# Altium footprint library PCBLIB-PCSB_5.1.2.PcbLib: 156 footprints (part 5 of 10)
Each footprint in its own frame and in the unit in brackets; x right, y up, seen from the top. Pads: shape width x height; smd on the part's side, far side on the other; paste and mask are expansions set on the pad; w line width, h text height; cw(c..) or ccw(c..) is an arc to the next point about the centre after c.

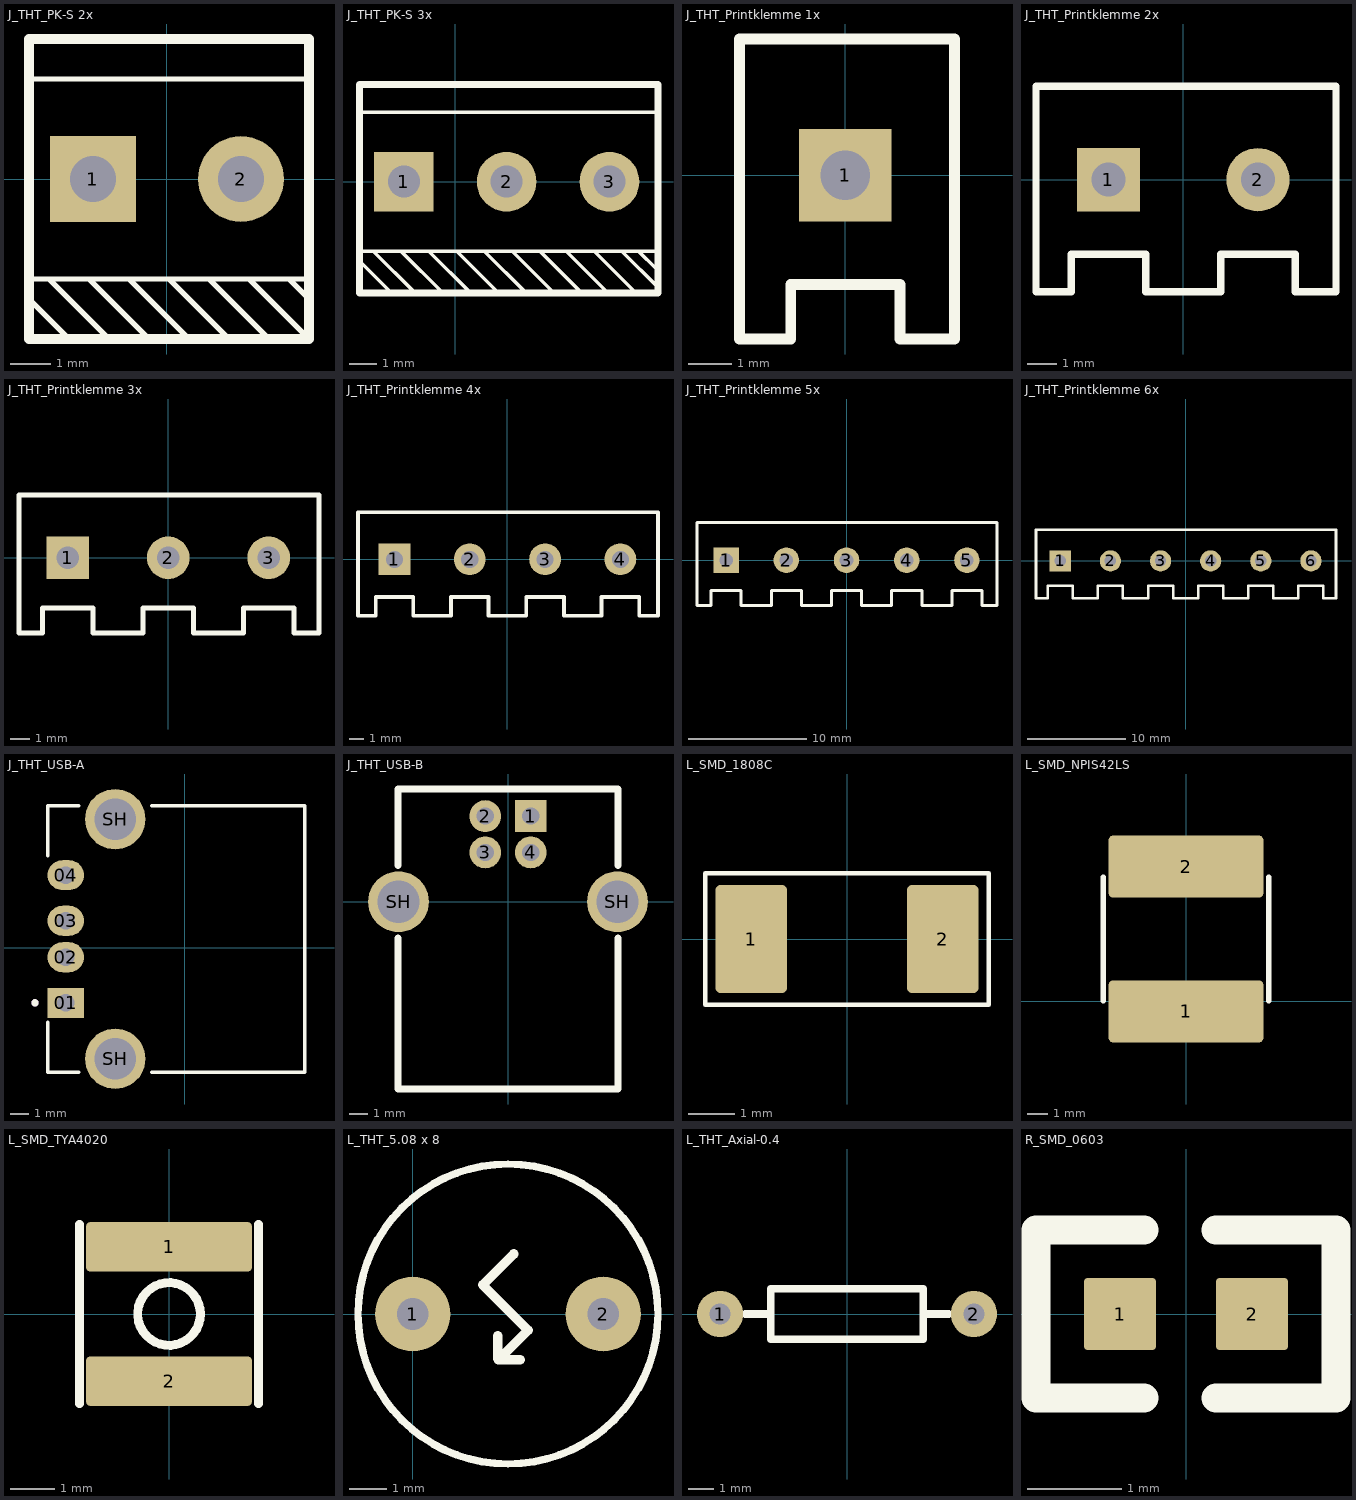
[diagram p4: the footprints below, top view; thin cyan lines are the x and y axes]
## J_THT_PK-S 2x [mm] "LB-2024-05-03g"
pads (2):
  rect 2.15x2.15 hole 1.15: 1(-1.85,0)
  round 2.15 hole 1.15: 2(1.85,0)
Top Overlay:
  lines w0.127: -3.45,2.5 3.55,2.5 ; -2.45,-4 -3.45,-3 -3.45,-2.5 3.55,-2.5 ; -1.95,-2.5 -0.45,-4 ; -1.45,-4 -2.95,-2.5 ; -0.95,-2.5 0.55,-4 ; 0.05,-2.5 1.55,-4 ; 1.05,-2.5 2.55,-4 ; 3.55,-4 2.05,-2.5 ; 3.55,-3 3.05,-2.5 ; -2.95,-2.5 -2.95,-2.5 ; 2.05,-2.5 2.05,-2.5 ; 3.05,-2.5 3.05,-2.5 ; 3.05,-2.5 3.05,-2.5
  lines w0.254: -3.45,-4 -2.91,-4 3.55,-4 3.55,3.5 -3.45,3.5 -3.45,2.365 -3.45,-4

## J_THT_PK-S 3x [mm] "LB-2024-05-03g"
pads (3):
  rect 2.15x2.15 hole 1.15: 1(-1.85,0)
  round 2.15 hole 1.15: 2(1.85,0) 3(5.55,0)
Top Overlay:
  lines w0.127: -3.5,-2.5 6.5,-2.5 7.3,-2.5 ; -3.45,2.5 7.3,2.5 ; -3.4,-2.9 -2.3,-4 ; -1.95,-2.5 -0.45,-4 ; -1.45,-4 -2.95,-2.5 ; -0.95,-2.5 0.55,-4 ; 0.05,-2.5 1.55,-4 ; 1.05,-2.5 2.55,-4 ; 3.55,-4 2.05,-2.5 ; 4,-2.5 5.425,-3.925 ; 4.575,-4.025 3.05,-2.5 ; 5,-2.5 6.5,-4 ; 6,-2.5 7.3,-3.8 ; 7,-2.5 6.6,-2.5 7.25,-3.15 ; -2.95,-2.5 -2.95,-2.5 ; 2.05,-2.5 2.05,-2.5 ; 3.05,-2.5 3.05,-2.5 ; 3.05,-2.5 3.05,-2.5
  lines w0.254: -3.45,-4 -2.91,-4 3.55,-4 7.3,-4 7.3,3.5 -3.45,3.5 -3.45,2.365 -3.45,-4

## J_THT_Printklemme 1x [mm] "LB-2024-04-17"
pads (1):
  rect 2.15x2.15 hole 1.15: 1(0,0)
Top Overlay:
  lines w0.254: -2.46,-3.81 -1.27,-3.81 -1.27,-2.54 1.27,-2.54 1.27,-3.81 2.54,-3.81 2.54,3.175 -2.46,3.175 -2.46,2.365 -2.46,-3.81

## J_THT_Printklemme 2x [mm] "LB-2024-04-17"
pads (2):
  rect 2.15x2.15 hole 1.15: 1(-2.54,0)
  round 2.15 hole 1.15: 2(2.54,0)
Top Overlay:
  lines w0.254: 1.27,-3.81 1.27,-2.54 ; 1.27,-3.81 -1.27,-3.81 -1.27,-2.54 -3.81,-2.54 -3.81,-3.81 -5,-3.81 -5,2.365 -5,3.175 5.19,3.175 5.19,-3.81 3.81,-3.81 ; 1.27,-3.81 1.27,-2.54 ; 1.27,-2.54 3.81,-2.54 ; 3.81,-3.81 3.81,-2.54 ; 3.81,-3.81 3.81,-2.54

## J_THT_Printklemme 3x [mm] "LB-2024-04-17"
pads (3):
  rect 2.15x2.15 hole 1.15: 1(-5.08,0)
  round 2.15 hole 1.15: 2(0,0) 3(5.08,0)
Top Overlay:
  lines w0.254: -1.27,-3.81 -1.27,-2.54 ; -1.27,-3.81 -3.81,-3.81 -3.81,-2.54 -6.35,-2.54 -6.35,-3.81 -7.54,-3.81 -7.54,2.365 -7.54,3.175 2.65,3.175 7.62,3.175 7.62,-3.81 6.35,-3.81 6.35,-2.54 3.81,-2.54 3.81,-3.81 1.27,-3.81 ; -1.27,-3.81 -1.27,-2.54 ; -1.27,-2.54 1.27,-2.54 ; 1.27,-3.81 1.27,-2.54 ; 1.27,-3.81 1.27,-2.54

## J_THT_Printklemme 4x [mm] "LB-2024-04-17"
pads (4):
  rect 2.15x2.15 hole 1.15: 1(-7.62,0)
  round 2.15 hole 1.15: 2(-2.54,0) 3(2.54,0) 4(7.62,0)
Top Overlay:
  lines w0.254: -3.81,-3.81 -3.81,-2.54 ; -3.81,-3.81 -6.35,-3.81 -6.35,-2.54 -8.89,-2.54 -8.89,-3.81 -10.08,-3.81 -10.08,2.365 -10.08,3.175 0.11,3.175 10.16,3.175 10.16,-3.81 8.89,-3.81 8.89,-2.54 6.35,-2.54 6.35,-3.81 3.81,-3.81 3.81,-2.54 1.27,-2.54 1.27,-3.81 -1.27,-3.81 ; -3.81,-3.81 -3.81,-2.54 ; -3.81,-2.54 -1.27,-2.54 ; -1.27,-3.81 -1.27,-2.54 ; -1.27,-3.81 -1.27,-2.54

## J_THT_Printklemme 5x [mm] "LB-2024-04-17"
pads (5):
  rect 2.15x2.15 hole 1.15: 1(-10.16,0)
  round 2.15 hole 1.15: 2(-5.08,0) 3(0,0) 4(5.08,0) 5(10.16,0)
Top Overlay:
  lines w0.254: -6.35,-3.81 -6.35,-2.54 ; -6.35,-3.81 -8.89,-3.81 -8.89,-2.54 -11.43,-2.54 -11.43,-3.81 -12.62,-3.81 -12.62,2.365 -12.62,3.175 -2.43,3.175 12.7,3.175 12.7,-3.81 11.43,-3.81 11.43,-2.54 8.89,-2.54 8.89,-3.81 6.35,-3.81 6.35,-2.54 3.81,-2.54 3.81,-3.81 1.27,-3.81 1.27,-2.54 -1.27,-2.54 -1.27,-3.81 -3.81,-3.81 ; -6.35,-3.81 -6.35,-2.54 ; -6.35,-2.54 -3.81,-2.54 ; -3.81,-3.81 -3.81,-2.54 ; -3.81,-3.81 -3.81,-2.54

## J_THT_Printklemme 6x [mm] "LB-2024-04-17"
pads (6):
  rect 2.15x2.15 hole 1.15: 1(-12.7,0)
  round 2.15 hole 1.15: 2(-7.62,0) 3(-2.54,0) 4(2.54,0) 5(7.62,0) 6(12.7,0)
Top Overlay:
  lines w0.254: -8.89,-3.81 -8.89,-2.54 ; -8.89,-3.81 -11.43,-3.81 -11.43,-2.54 -13.97,-2.54 -13.97,-3.81 -15.16,-3.81 -15.16,2.365 -15.16,3.175 -4.97,3.175 15.24,3.175 15.24,-3.81 13.97,-3.81 13.97,-2.54 11.43,-2.54 11.43,-3.81 8.89,-3.81 8.89,-2.54 6.35,-2.54 6.35,-3.81 3.81,-3.81 3.81,-2.54 1.27,-2.54 1.27,-3.81 -1.27,-3.81 -1.27,-2.54 -3.81,-2.54 -3.81,-3.81 -6.35,-3.81 ; -8.89,-3.81 -8.89,-2.54 ; -8.89,-2.54 -6.35,-2.54 ; -6.35,-3.81 -6.35,-2.54 ; -6.35,-3.81 -6.35,-2.54

## J_THT_USB-A [mm] "LB-2024-04-29"
pads (6):
  rect 2x1.65 hole 0.95: 01(-6.536,-3.032)
  oval 2x1.65 hole 0.95: 02(-6.536,-0.532) 03(-6.536,1.468) 04(-6.536,3.968)
  round 3.316 hole 2.3: SH(-3.826,-6.102) SH(-3.826,7.038)
Top Overlay:
  circle w0.2: c-8.226,-3.032 r0.1
  lines w0.2: -7.526,-4.097 -7.526,-6.832 -5.836,-6.832 ; -7.526,5.033 -7.526,7.768 -5.836,7.768 ; -1.816,-6.832 6.574,-6.832 6.574,7.768 -1.816,7.768
Mechanical 13:
  circle w0.2: c-8.226,-3.032 r0.1

## J_THT_USB-B [mm] "LB-2024-04-15"
pads (6):
  rect 1.75x1.75 hole 0.95: 1(1.25,4.71)
  round 1.75 hole 0.95: 2(-1.25,4.71) 3(-1.25,2.71) 4(1.25,2.71)
  round 3.346 hole 2.33: SH(-6.02,0) SH(6.02,0)
Top Overlay:
  lines w0.4: -6.05,-2 -6.05,-10.3 6.05,-10.3 6.05,-2 ; -6.05,2 -6.05,6.2 6.05,6.2 6.05,2

## L_SMD_1808C [mm] "LB-2024-04-17"
height 2
pads (2):
  rrect15% 1.55x2.35 smd paste-0.02 mask+0.05: 1(-2.075,0) 2(2.075,0)
Top Overlay:
  lines w0.1: -3.075,-1.425 -3.075,1.425 3.075,1.425 3.075,-1.425 -3.075,-1.425

## L_SMD_NPIS42LS [mm] "LB-2024-04-17"
pads (2):
  rrect15% 7.5x3 smd paste-0.02 mask+0.05: 1(0,-0.5) 2(0,6.5)
Top Overlay:
  lines w0.254: -4,0 -4,3 -4,6 ; 4,0 4,3 4,6

## L_SMD_TYA4020 [mm] "LB-2024-04-25"
height 2.1
pads (2):
  rrect15% 3.7x1.1 smd paste-0.02 mask+0.05: 1(0,1.5) 2(0,-1.5)
Top Overlay:
  circle w0.2: c0,0 r0.7
  lines w0.2: -2,-2 -2,0 -2,2 ; 2,-2 2,0 2,2

## L_THT_5.08 x 8 [mm] "LB-2024-04-17"
pads (2):
  round 2 hole 0.85: 1(0,0) 2(5.08,0)
Top Overlay:
  circle w0.2: c2.54,0 r4
  lines w0.254: 2.261,-0.762 2.261,-1.194 ; 2.261,-0.584 2.261,-1.194 ; 2.692,1.6 1.867,0.775 3.073,-0.432 2.286,-1.219 ; 2.261,-1.194 2.286,-1.219 ; 2.286,-1.219 2.87,-1.219 ; 2.286,-1.219 2.87,-1.219 ; 2.286,-1.219 2.87,-1.219

## L_THT_Axial-0.4 [mm]
pads (2):
  round 1.85 hole 0.85: 1(-5.08,0) 2(5.08,0)
Top Overlay:
  lines w0.305: -4.064,0 -3.048,0 ; 3.048,0 4.064,0 ; -3.048,-1.016 3.048,-1.016 3.048,1.016 -3.048,1.016 -3.048,-1.016

## R_SMD_0603 [mil] "LB-2024-04-17"
pads (2):
  rrect10% 30x30 smd paste-0.79 mask+1.97: 1(-27.5,0) 2(27.5,0)
Top Overlay:
  lines w12: -17.5,-35 -62.5,-35 -62.5,35 -17.5,35 ; 12.5,-35 62.5,-35 62.5,35 12.5,35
